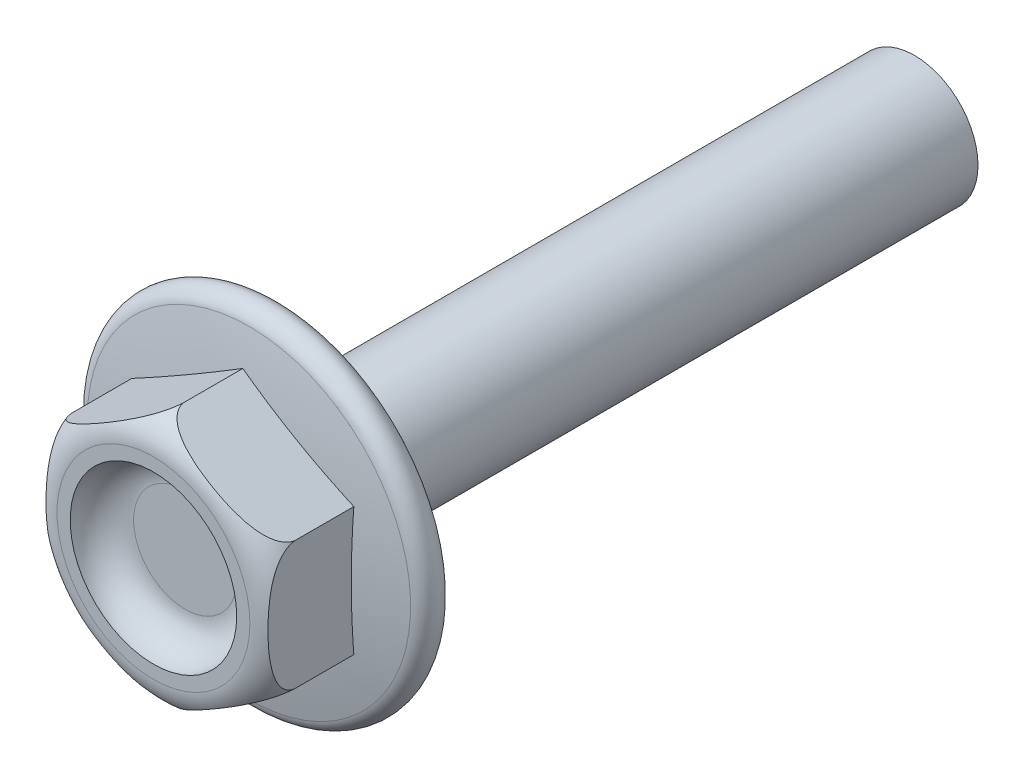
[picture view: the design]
ISO-10303-21;
HEADER;
FILE_DESCRIPTION(('STEP AP214'),'2;1');
FILE_NAME('part.step','',(''),(''),'','','');
FILE_SCHEMA(('AUTOMOTIVE_DESIGN { 1 0 10303 214 1 1 1 1 }'));
ENDSEC;
DATA;
#1=APPLICATION_CONTEXT('core data for automotive mechanical design processes');
#2=APPLICATION_PROTOCOL_DEFINITION('international standard','automotive_design',2000,#1);
#3=PRODUCT_CONTEXT('',#1,'mechanical');
#4=PRODUCT('Part','Part','',(#3));
#5=PRODUCT_RELATED_PRODUCT_CATEGORY('part','',(#4));
#6=PRODUCT_DEFINITION_FORMATION('','',#4);
#7=PRODUCT_DEFINITION_CONTEXT('part definition',#1,'design');
#8=PRODUCT_DEFINITION('design','',#6,#7);
#9=PRODUCT_DEFINITION_SHAPE('','',#8);
#10=(LENGTH_UNIT() NAMED_UNIT(*) SI_UNIT(.MILLI.,.METRE.));
#11=(NAMED_UNIT(*) PLANE_ANGLE_UNIT() SI_UNIT($,.RADIAN.));
#12=(NAMED_UNIT(*) SI_UNIT($,.STERADIAN.) SOLID_ANGLE_UNIT());
#13=UNCERTAINTY_MEASURE_WITH_UNIT(LENGTH_MEASURE(1.E-05),#10,'distance_accuracy_value','');
#14=(GEOMETRIC_REPRESENTATION_CONTEXT(3) GLOBAL_UNCERTAINTY_ASSIGNED_CONTEXT((#13)) GLOBAL_UNIT_ASSIGNED_CONTEXT((#10,
#11,#12)) REPRESENTATION_CONTEXT('',''));
#15=CARTESIAN_POINT('',(0.,0.,0.));
#16=DIRECTION('',(0.,0.,1.));
#17=DIRECTION('',(1.,0.,0.));
#18=AXIS2_PLACEMENT_3D('',#15,#16,#17);
#19=CARTESIAN_POINT('',(0.,4.04145188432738,4.));
#20=DIRECTION('',(0.500000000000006,0.866025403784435,0.));
#21=DIRECTION('',(-0.866025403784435,0.500000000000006,0.));
#22=AXIS2_PLACEMENT_3D('',#19,#20,#21);
#23=PLANE('',#22);
#24=DIRECTION('',(0.,0.,-1.));
#25=VECTOR('',#24,1.);
#26=CARTESIAN_POINT('',(0.,4.04145188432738,4.));
#27=LINE('',#26,#25);
#28=CARTESIAN_POINT('',(0.,4.04145188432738,3.));
#29=VERTEX_POINT('',#28);
#30=CARTESIAN_POINT('',(0.,4.04145188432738,1.18087034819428));
#31=VERTEX_POINT('',#30);
#32=EDGE_CURVE('E51',#29,#31,#27,.T.);
#33=ORIENTED_EDGE('',*,*,#32,.F.);
#34=CARTESIAN_POINT('',(3.46410156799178E-08,4.04145186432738,2.9998));
#35=CARTESIAN_POINT('',(-6.54132162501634E-05,4.04148965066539,3.02946004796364));
#36=CARTESIAN_POINT('',(0.00226144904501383,4.04014623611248,3.05905658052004));
#37=CARTESIAN_POINT('',(0.0112266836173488,4.03497015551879,3.11713737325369));
#38=CARTESIAN_POINT('',(0.0178312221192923,4.03115702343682,3.14562851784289));
#39=CARTESIAN_POINT('',(0.0348712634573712,4.02131895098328,3.20093447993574));
#40=CARTESIAN_POINT('',(0.0452976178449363,4.01529929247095,3.22775312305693));
#41=CARTESIAN_POINT('',(0.0693600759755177,4.0014068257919,3.27943202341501));
#42=CARTESIAN_POINT('',(0.0830027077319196,3.99353024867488,3.30428815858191));
#43=CARTESIAN_POINT('',(0.121428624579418,3.97134503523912,3.36543474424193));
#44=CARTESIAN_POINT('',(0.148119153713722,3.95593525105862,3.40012716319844));
#45=CARTESIAN_POINT('',(0.205872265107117,3.9225914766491,3.46423943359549));
#46=CARTESIAN_POINT('',(0.23694539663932,3.90465139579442,3.49364616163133));
#47=CARTESIAN_POINT('',(0.323036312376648,3.85494678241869,3.5651961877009));
#48=CARTESIAN_POINT('',(0.380554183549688,3.82173882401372,3.60329409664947));
#49=CARTESIAN_POINT('',(0.499668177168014,3.75296832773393,3.66943708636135));
#50=CARTESIAN_POINT('',(0.561272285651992,3.71740117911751,3.69746175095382));
#51=CARTESIAN_POINT('',(0.70657163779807,3.6335125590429,3.75351666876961));
#52=CARTESIAN_POINT('',(0.791067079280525,3.5847290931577,3.77871981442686));
#53=CARTESIAN_POINT('',(0.961803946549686,3.48615411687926,3.81977186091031));
#54=CARTESIAN_POINT('',(1.04804876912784,3.43636064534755,3.83560030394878));
#55=CARTESIAN_POINT('',(1.22192619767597,3.33597246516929,3.8605608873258));
#56=CARTESIAN_POINT('',(1.3095643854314,3.2853745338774,3.86963887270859));
#57=CARTESIAN_POINT('',(1.48502337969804,3.18407323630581,3.88252309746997));
#58=CARTESIAN_POINT('',(1.57284392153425,3.13337002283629,3.88633451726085));
#59=CARTESIAN_POINT('',(1.75592877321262,3.02766593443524,3.88956421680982));
#60=CARTESIAN_POINT('',(1.85119817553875,2.97266211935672,3.88858622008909));
#61=CARTESIAN_POINT('',(2.04168348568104,2.86268537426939,3.88109833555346));
#62=CARTESIAN_POINT('',(2.1368992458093,2.80771252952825,3.87458294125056));
#63=CARTESIAN_POINT('',(2.32594109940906,2.69856916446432,3.85466572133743));
#64=CARTESIAN_POINT('',(2.41977196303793,2.64439589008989,3.84132691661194));
#65=CARTESIAN_POINT('',(2.60599333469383,2.53688093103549,3.80514232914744));
#66=CARTESIAN_POINT('',(2.69838642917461,2.48353775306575,3.78231634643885));
#67=CARTESIAN_POINT('',(2.8368207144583,2.40361268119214,3.73693902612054));
#68=CARTESIAN_POINT('',(2.88407819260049,2.37632856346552,3.71938388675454));
#69=CARTESIAN_POINT('',(2.97718566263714,2.3225729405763,3.67952045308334));
#70=CARTESIAN_POINT('',(3.02303335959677,2.29610276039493,3.65720483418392));
#71=CARTESIAN_POINT('',(3.1126878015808,2.2443407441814,3.60659866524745));
#72=CARTESIAN_POINT('',(3.15647528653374,2.21906002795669,3.57826174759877));
#73=CARTESIAN_POINT('',(3.24002372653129,2.17082331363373,3.5144939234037));
#74=CARTESIAN_POINT('',(3.27979325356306,2.14786236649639,3.47907862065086));
#75=CARTESIAN_POINT('',(3.33931362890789,2.11349826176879,3.4146055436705));
#76=CARTESIAN_POINT('',(3.36104751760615,2.10095019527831,3.38800019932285));
#77=CARTESIAN_POINT('',(3.40092876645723,2.07792474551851,3.33138585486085));
#78=CARTESIAN_POINT('',(3.41907945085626,2.06744544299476,3.30138005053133));
#79=CARTESIAN_POINT('',(3.44834249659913,2.0505504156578,3.24278652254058));
#80=CARTESIAN_POINT('',(3.46009477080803,2.04376523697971,3.21462807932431));
#81=CARTESIAN_POINT('',(3.47936142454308,2.03264162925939,3.15645553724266));
#82=CARTESIAN_POINT('',(3.48688485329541,2.028297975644,3.12644555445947));
#83=CARTESIAN_POINT('',(3.49465097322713,2.02381420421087,3.08009860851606));
#84=CARTESIAN_POINT('',(3.49665509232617,2.02265712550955,3.06413628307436));
#85=CARTESIAN_POINT('',(3.49933449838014,2.02111016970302,3.03205266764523));
#86=CARTESIAN_POINT('',(3.50000884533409,2.02072083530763,3.01593127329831));
#87=CARTESIAN_POINT('',(3.49999996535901,2.02072596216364,2.9998));
#88=B_SPLINE_CURVE_WITH_KNOTS('',3,(#34,#35,#36,#37,#38,#39,#40,#41,#42,#43,#44,#45,#46,#47,#48,
#49,#50,#51,#52,#53,#54,#55,#56,#57,#58,#59,#60,#61,#62,#63,#64,#65,#66,#67,#68,#69,#70,#71,#72,
#73,#74,#75,#76,#77,#78,#79,#80,#81,#82,#83,#84,#85,#86,#87),.UNSPECIFIED.,.F.,.F.,(4,2,2,2,2,2,
2,2,2,2,2,2,2,2,2,2,2,2,2,2,2,2,2,2,2,2,4),(0.,0.0887549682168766,0.176816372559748,
0.264668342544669,0.352700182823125,0.491116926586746,0.629872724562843,0.858271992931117,
1.08713159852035,1.38870326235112,1.69093062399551,1.99555716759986,2.29988385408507,
2.62979570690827,2.96003601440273,3.28727986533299,3.61384415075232,3.78564861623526,
3.95771935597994,4.13116655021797,4.30423552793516,4.41365097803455,4.52296443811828,
4.61636709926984,4.70956912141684,4.75789060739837,4.8062462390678),.UNSPECIFIED.);
#89=CARTESIAN_POINT('',(3.49999999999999,2.0207259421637,3.));
#90=VERTEX_POINT('',#89);
#91=EDGE_CURVE('E44',#29,#90,#88,.T.);
#92=ORIENTED_EDGE('',*,*,#91,.T.);
#93=DIRECTION('',(0.,0.,-1.));
#94=VECTOR('',#93,1.);
#95=CARTESIAN_POINT('',(3.49999999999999,2.02072594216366,4.));
#96=LINE('',#95,#94);
#97=CARTESIAN_POINT('',(3.49999999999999,2.02072594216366,1.18087034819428));
#98=VERTEX_POINT('',#97);
#99=EDGE_CURVE('E92',#90,#98,#96,.T.);
#100=ORIENTED_EDGE('',*,*,#99,.T.);
#101=CARTESIAN_POINT('',(1.75000000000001,3.0310889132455,-24.25));
#102=DIRECTION('',(0.500000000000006,0.866025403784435,0.));
#103=DIRECTION('',(-0.866025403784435,0.500000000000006,0.));
#104=AXIS2_PLACEMENT_3D('',#101,#102,#103);
#105=CIRCLE('',#104,25.5110270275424);
#106=EDGE_CURVE('E111',#98,#31,#105,.F.);
#107=ORIENTED_EDGE('',*,*,#106,.T.);
#108=EDGE_LOOP('',(#33,#92,#100,#107));
#109=FACE_BOUND('',#108,.T.);
#110=ADVANCED_FACE('F28',(#109),#23,.T.);
#111=CARTESIAN_POINT('',(3.49999999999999,2.02072594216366,4.));
#112=DIRECTION('',(1.,0.,0.));
#113=DIRECTION('',(0.,1.,0.));
#114=AXIS2_PLACEMENT_3D('',#111,#112,#113);
#115=PLANE('',#114);
#116=ORIENTED_EDGE('',*,*,#99,.F.);
#117=CARTESIAN_POINT('',(3.49999999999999,0.,3.88866958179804));
#118=CARTESIAN_POINT('',(3.49999999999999,-0.0863268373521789,3.88866475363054));
#119=CARTESIAN_POINT('',(3.49999999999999,-0.172651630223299,3.88703903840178));
#120=CARTESIAN_POINT('',(3.49999999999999,-0.345200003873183,3.88029865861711));
#121=CARTESIAN_POINT('',(3.49999999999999,-0.431423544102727,3.87518289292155));
#122=CARTESIAN_POINT('',(3.49999999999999,-0.603354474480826,3.86079550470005));
#123=CARTESIAN_POINT('',(3.49999999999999,-0.689062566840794,3.85153259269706));
#124=CARTESIAN_POINT('',(3.49999999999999,-0.859711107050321,3.82768385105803));
#125=CARTESIAN_POINT('',(3.49999999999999,-0.944652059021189,3.81310182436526));
#126=CARTESIAN_POINT('',(3.49999999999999,-1.10047939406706,3.77956527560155));
#127=CARTESIAN_POINT('',(3.49999999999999,-1.17157101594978,3.7615884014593));
#128=CARTESIAN_POINT('',(3.49999999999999,-1.31198004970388,3.71895615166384));
#129=CARTESIAN_POINT('',(3.49999999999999,-1.38129291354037,3.69428522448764));
#130=CARTESIAN_POINT('',(3.49999999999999,-1.51730819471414,3.63592514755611));
#131=CARTESIAN_POINT('',(3.49999999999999,-1.58395793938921,3.60210997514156));
#132=CARTESIAN_POINT('',(3.49999999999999,-1.71012924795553,3.52311771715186));
#133=CARTESIAN_POINT('',(3.49999999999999,-1.76969019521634,3.47800819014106));
#134=CARTESIAN_POINT('',(3.49999999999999,-1.84774561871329,3.40145225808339));
#135=CARTESIAN_POINT('',(3.49999999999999,-1.87138500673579,3.3752636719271));
#136=CARTESIAN_POINT('',(3.49999999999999,-1.91465839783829,3.31970869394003));
#137=CARTESIAN_POINT('',(3.49999999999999,-1.93429275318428,3.2903425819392));
#138=CARTESIAN_POINT('',(3.49999999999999,-1.96851600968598,3.228316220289));
#139=CARTESIAN_POINT('',(3.49999999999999,-1.98304564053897,3.19562261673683));
#140=CARTESIAN_POINT('',(3.49999999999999,-2.0054250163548,3.12802070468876));
#141=CARTESIAN_POINT('',(3.49999999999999,-2.01328508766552,3.09311591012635));
#142=CARTESIAN_POINT('',(3.49999999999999,-2.02095945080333,3.02693329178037));
#143=CARTESIAN_POINT('',(3.49999999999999,-2.02166949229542,2.99575843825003));
#144=CARTESIAN_POINT('',(3.49999999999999,-2.01730141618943,2.93381941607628));
#145=CARTESIAN_POINT('',(3.49999999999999,-2.01222343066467,2.90305523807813));
#146=CARTESIAN_POINT('',(3.49999999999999,-1.99739983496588,2.84550196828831));
#147=CARTESIAN_POINT('',(3.49999999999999,-1.98808984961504,2.81859776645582));
#148=CARTESIAN_POINT('',(3.49999999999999,-1.96561338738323,2.76647205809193));
#149=CARTESIAN_POINT('',(3.49999999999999,-1.95244609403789,2.74125090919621));
#150=CARTESIAN_POINT('',(3.49999999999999,-1.91585963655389,2.68119414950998));
#151=CARTESIAN_POINT('',(3.49999999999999,-1.89054654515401,2.64751269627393));
#152=CARTESIAN_POINT('',(3.49999999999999,-1.83488053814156,2.58459756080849));
#153=CARTESIAN_POINT('',(3.49999999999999,-1.80451416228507,2.55537616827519));
#154=CARTESIAN_POINT('',(3.49999999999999,-1.72189631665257,2.48560726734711));
#155=CARTESIAN_POINT('',(3.49999999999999,-1.66706197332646,2.4481420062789));
#156=CARTESIAN_POINT('',(3.49999999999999,-1.55256598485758,2.38180725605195));
#157=CARTESIAN_POINT('',(3.49999999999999,-1.49289865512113,2.35294808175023));
#158=CARTESIAN_POINT('',(3.49999999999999,-1.3721212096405,2.30262557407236));
#159=CARTESIAN_POINT('',(3.49999999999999,-1.31107157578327,2.28101370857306));
#160=CARTESIAN_POINT('',(3.49999999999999,-1.18734677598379,2.24298388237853));
#161=CARTESIAN_POINT('',(3.49999999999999,-1.12466994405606,2.22657149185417));
#162=CARTESIAN_POINT('',(3.49999999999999,-0.997959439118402,2.19781531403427));
#163=CARTESIAN_POINT('',(3.49999999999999,-0.933919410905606,2.18550018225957));
#164=CARTESIAN_POINT('',(3.49999999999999,-0.805330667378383,2.16427101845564));
#165=CARTESIAN_POINT('',(3.49999999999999,-0.740782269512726,2.15535501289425));
#166=CARTESIAN_POINT('',(3.49999999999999,-0.598058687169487,2.13873267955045));
#167=CARTESIAN_POINT('',(3.49999999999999,-0.519811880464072,2.13165251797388));
#168=CARTESIAN_POINT('',(3.49999999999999,-0.36308132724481,2.12073868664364));
#169=CARTESIAN_POINT('',(3.49999999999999,-0.284597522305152,2.11690589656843));
#170=CARTESIAN_POINT('',(3.49999999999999,-0.127339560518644,2.11205625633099));
#171=CARTESIAN_POINT('',(3.49999999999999,-0.0485651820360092,2.11104681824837));
#172=CARTESIAN_POINT('',(3.49999999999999,0.108959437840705,2.11174847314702));
#173=CARTESIAN_POINT('',(3.49999999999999,0.18770968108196,2.11345913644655));
#174=CARTESIAN_POINT('',(3.49999999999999,0.344482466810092,2.11977175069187));
#175=CARTESIAN_POINT('',(3.49999999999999,0.42250589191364,2.12435103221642));
#176=CARTESIAN_POINT('',(3.49999999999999,0.578320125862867,2.13688479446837));
#177=CARTESIAN_POINT('',(3.49999999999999,0.656110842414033,2.14484047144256));
#178=CARTESIAN_POINT('',(3.49999999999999,0.810862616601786,2.1649235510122));
#179=CARTESIAN_POINT('',(3.49999999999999,0.887825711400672,2.17703484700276));
#180=CARTESIAN_POINT('',(3.49999999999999,1.04069181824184,2.20662161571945));
#181=CARTESIAN_POINT('',(3.49999999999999,1.11659576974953,2.22409197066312));
#182=CARTESIAN_POINT('',(3.49999999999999,1.22622138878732,2.25478752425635));
#183=CARTESIAN_POINT('',(3.49999999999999,1.26071408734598,2.26525722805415));
#184=CARTESIAN_POINT('',(3.49999999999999,1.32913620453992,2.28791589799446));
#185=CARTESIAN_POINT('',(3.49999999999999,1.36306544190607,2.30010540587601));
#186=CARTESIAN_POINT('',(3.49999999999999,1.46365216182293,2.33955916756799));
#187=CARTESIAN_POINT('',(3.49999999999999,1.52924178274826,2.369743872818));
#188=CARTESIAN_POINT('',(3.49999999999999,1.63826125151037,2.43070580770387));
#189=CARTESIAN_POINT('',(3.49999999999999,1.68295511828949,2.45920328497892));
#190=CARTESIAN_POINT('',(3.49999999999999,1.76768051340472,2.52254240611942));
#191=CARTESIAN_POINT('',(3.49999999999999,1.8077188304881,2.55737461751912));
#192=CARTESIAN_POINT('',(3.49999999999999,1.86880478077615,2.62179662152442));
#193=CARTESIAN_POINT('',(3.49999999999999,1.89183062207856,2.64950003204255));
#194=CARTESIAN_POINT('',(3.49999999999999,1.93330435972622,2.70815552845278));
#195=CARTESIAN_POINT('',(3.49999999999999,1.95175915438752,2.73910261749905));
#196=CARTESIAN_POINT('',(3.49999999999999,1.98020381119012,2.79847583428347));
#197=CARTESIAN_POINT('',(3.49999999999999,1.99108975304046,2.8264695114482));
#198=CARTESIAN_POINT('',(3.49999999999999,2.00802811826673,2.88389269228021));
#199=CARTESIAN_POINT('',(3.49999999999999,2.01408338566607,2.91332134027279));
#200=CARTESIAN_POINT('',(3.49999999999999,2.02088735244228,2.9729068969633));
#201=CARTESIAN_POINT('',(3.49999999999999,2.02161631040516,3.00306609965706));
#202=CARTESIAN_POINT('',(3.49999999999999,2.01765062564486,3.06302342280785));
#203=CARTESIAN_POINT('',(3.49999999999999,2.01295539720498,3.09282150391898));
#204=CARTESIAN_POINT('',(3.49999999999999,1.99894363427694,3.14951865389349));
#205=CARTESIAN_POINT('',(3.49999999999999,1.98990016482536,3.17648665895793));
#206=CARTESIAN_POINT('',(3.49999999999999,1.96792176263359,3.22877122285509));
#207=CARTESIAN_POINT('',(3.49999999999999,1.95498534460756,3.25408714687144));
#208=CARTESIAN_POINT('',(3.49999999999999,1.91910314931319,3.31410022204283));
#209=CARTESIAN_POINT('',(3.49999999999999,1.89430007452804,3.34768656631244));
#210=CARTESIAN_POINT('',(3.49999999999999,1.83966536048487,3.41047531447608));
#211=CARTESIAN_POINT('',(3.49999999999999,1.80982214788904,3.43966732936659));
#212=CARTESIAN_POINT('',(3.49999999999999,1.72878496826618,3.50921588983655));
#213=CARTESIAN_POINT('',(3.49999999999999,1.67504338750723,3.54658123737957));
#214=CARTESIAN_POINT('',(3.49999999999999,1.56265233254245,3.61290679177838));
#215=CARTESIAN_POINT('',(3.49999999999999,1.50399107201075,3.64184602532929));
#216=CARTESIAN_POINT('',(3.49999999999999,1.38547326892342,3.69227368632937));
#217=CARTESIAN_POINT('',(3.49999999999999,1.32569142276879,3.71394172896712));
#218=CARTESIAN_POINT('',(3.49999999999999,1.20448970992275,3.75217091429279));
#219=CARTESIAN_POINT('',(3.49999999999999,1.14306820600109,3.76872672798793));
#220=CARTESIAN_POINT('',(3.49999999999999,1.01920506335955,3.79774633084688));
#221=CARTESIAN_POINT('',(3.49999999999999,0.956762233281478,3.81020492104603));
#222=CARTESIAN_POINT('',(3.49999999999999,0.83129623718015,3.83179537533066));
#223=CARTESIAN_POINT('',(3.49999999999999,0.768272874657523,3.84092606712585));
#224=CARTESIAN_POINT('',(3.49999999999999,0.588181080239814,3.86310397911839));
#225=CARTESIAN_POINT('',(3.49999999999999,0.470713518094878,3.8728822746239));
#226=CARTESIAN_POINT('',(3.49999999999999,0.235495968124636,3.88566728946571));
#227=CARTESIAN_POINT('',(3.49999999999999,0.117746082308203,3.88867616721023));
#228=CARTESIAN_POINT('',(3.49999999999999,0.,3.88866958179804));
#229=B_SPLINE_CURVE_WITH_KNOTS('',3,(#117,#118,#119,#120,#121,#122,#123,#124,#125,#126,#127,
#128,#129,#130,#131,#132,#133,#134,#135,#136,#137,#138,#139,#140,#141,#142,#143,#144,#145,#146,
#147,#148,#149,#150,#151,#152,#153,#154,#155,#156,#157,#158,#159,#160,#161,#162,#163,#164,#165,
#166,#167,#168,#169,#170,#171,#172,#173,#174,#175,#176,#177,#178,#179,#180,#181,#182,#183,#184,
#185,#186,#187,#188,#189,#190,#191,#192,#193,#194,#195,#196,#197,#198,#199,#200,#201,#202,#203,
#204,#205,#206,#207,#208,#209,#210,#211,#212,#213,#214,#215,#216,#217,#218,#219,#220,#221,#222,
#223,#224,#225,#226,#227,#228),.UNSPECIFIED.,.T.,.F.,(4,2,2,2,2,2,2,2,2,2,2,2,2,2,2,2,2,2,2,2,2,
2,2,2,2,2,2,2,2,2,2,2,2,2,2,2,2,2,2,2,2,2,2,2,2,2,2,2,2,2,2,2,2,2,2,4),(0.,0.258960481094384,
0.518002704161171,0.776503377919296,1.03481959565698,1.25457530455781,1.47484598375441,
1.69832240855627,1.92049274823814,2.02603918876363,2.13157634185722,2.23830124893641,
2.34486061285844,2.43787441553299,2.53088609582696,2.61595499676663,2.7010419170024,
2.82672538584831,2.95274915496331,3.15085859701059,3.34920453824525,3.54319361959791,
3.73738982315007,3.93291697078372,4.12833042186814,4.36394350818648,4.59962039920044,
4.83591542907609,5.07217313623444,5.30658695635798,5.5410838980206,5.77468204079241,
6.0080577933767,6.11615522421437,6.22428678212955,6.44013860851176,6.59875051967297,
6.75712816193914,6.86485155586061,6.9724113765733,7.06214192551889,7.15181960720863,
7.24182950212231,7.33184911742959,7.4168355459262,7.50185444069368,7.62640196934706,
7.75123947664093,7.94649755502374,8.14223757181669,8.33270789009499,8.52337608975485,
8.71428530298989,8.9052617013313,9.25858529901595,9.61179622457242),.UNSPECIFIED.);
#230=CARTESIAN_POINT('',(3.49999999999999,-2.0207259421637,3.));
#231=VERTEX_POINT('',#230);
#232=EDGE_CURVE('E81',#90,#231,#229,.T.);
#233=ORIENTED_EDGE('',*,*,#232,.T.);
#234=DIRECTION('',(0.,0.,-1.));
#235=VECTOR('',#234,1.);
#236=CARTESIAN_POINT('',(3.49999999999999,-2.0207259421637,4.));
#237=LINE('',#236,#235);
#238=CARTESIAN_POINT('',(3.49999999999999,-2.0207259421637,1.18087034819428));
#239=VERTEX_POINT('',#238);
#240=EDGE_CURVE('E100',#231,#239,#237,.T.);
#241=ORIENTED_EDGE('',*,*,#240,.T.);
#242=CARTESIAN_POINT('',(3.49999999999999,0.,-24.25));
#243=DIRECTION('',(1.,0.,0.));
#244=DIRECTION('',(0.,1.,0.));
#245=AXIS2_PLACEMENT_3D('',#242,#243,#244);
#246=CIRCLE('',#245,25.5110270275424);
#247=EDGE_CURVE('E99',#239,#98,#246,.F.);
#248=ORIENTED_EDGE('',*,*,#247,.T.);
#249=EDGE_LOOP('',(#116,#233,#241,#248));
#250=FACE_BOUND('',#249,.T.);
#251=ADVANCED_FACE('F97',(#250),#115,.T.);
#252=CARTESIAN_POINT('',(3.49999999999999,-2.0207259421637,4.));
#253=DIRECTION('',(0.499999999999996,-0.866025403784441,0.));
#254=DIRECTION('',(0.866025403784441,0.499999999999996,0.));
#255=AXIS2_PLACEMENT_3D('',#252,#253,#254);
#256=PLANE('',#255);
#257=ORIENTED_EDGE('',*,*,#240,.F.);
#258=CARTESIAN_POINT('',(3.49999996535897,-2.0207259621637,2.9998));
#259=CARTESIAN_POINT('',(3.50006541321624,-2.02068817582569,3.02946004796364));
#260=CARTESIAN_POINT('',(3.49773855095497,-2.0220315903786,3.05905658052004));
#261=CARTESIAN_POINT('',(3.48877331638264,-2.02720767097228,3.11713737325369));
#262=CARTESIAN_POINT('',(3.48216877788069,-2.03102080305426,3.14562851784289));
#263=CARTESIAN_POINT('',(3.46512873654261,-2.0408588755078,3.20093447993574));
#264=CARTESIAN_POINT('',(3.45470238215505,-2.04687853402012,3.22775312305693));
#265=CARTESIAN_POINT('',(3.43063992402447,-2.06077100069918,3.27943202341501));
#266=CARTESIAN_POINT('',(3.41699729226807,-2.06864757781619,3.3042881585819));
#267=CARTESIAN_POINT('',(3.37857137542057,-2.09083279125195,3.36543474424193));
#268=CARTESIAN_POINT('',(3.35188084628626,-2.10624257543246,3.40012716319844));
#269=CARTESIAN_POINT('',(3.29412773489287,-2.13958634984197,3.46423943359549));
#270=CARTESIAN_POINT('',(3.26305460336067,-2.15752643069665,3.49364616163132));
#271=CARTESIAN_POINT('',(3.17696368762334,-2.20723104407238,3.56519618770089));
#272=CARTESIAN_POINT('',(3.1194458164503,-2.24043900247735,3.60329409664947));
#273=CARTESIAN_POINT('',(3.00033182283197,-2.30920949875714,3.66943708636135));
#274=CARTESIAN_POINT('',(2.93872771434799,-2.34477664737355,3.69746175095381));
#275=CARTESIAN_POINT('',(2.79342836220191,-2.42866526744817,3.75351666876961));
#276=CARTESIAN_POINT('',(2.70893292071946,-2.47744873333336,3.77871981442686));
#277=CARTESIAN_POINT('',(2.5381960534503,-2.5760237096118,3.8197718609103));
#278=CARTESIAN_POINT('',(2.45195123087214,-2.62581718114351,3.83560030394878));
#279=CARTESIAN_POINT('',(2.27807380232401,-2.72620536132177,3.86056088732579));
#280=CARTESIAN_POINT('',(2.19043561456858,-2.77680329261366,3.86963887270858));
#281=CARTESIAN_POINT('',(2.01497662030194,-2.87810459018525,3.88252309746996));
#282=CARTESIAN_POINT('',(1.92715607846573,-2.92880780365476,3.88633451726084));
#283=CARTESIAN_POINT('',(1.74407122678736,-3.03451189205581,3.88956421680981));
#284=CARTESIAN_POINT('',(1.64880182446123,-3.08951570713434,3.88858622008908));
#285=CARTESIAN_POINT('',(1.45831651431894,-3.19949245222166,3.88109833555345));
#286=CARTESIAN_POINT('',(1.36310075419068,-3.2544652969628,3.87458294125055));
#287=CARTESIAN_POINT('',(1.17405890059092,-3.36360866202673,3.85466572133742));
#288=CARTESIAN_POINT('',(1.08022803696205,-3.41778193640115,3.84132691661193));
#289=CARTESIAN_POINT('',(0.894006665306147,-3.52529689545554,3.80514232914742));
#290=CARTESIAN_POINT('',(0.801613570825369,-3.57864007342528,3.78231634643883));
#291=CARTESIAN_POINT('',(0.663179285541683,-3.65856514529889,3.73693902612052));
#292=CARTESIAN_POINT('',(0.615921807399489,-3.68584926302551,3.71938388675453));
#293=CARTESIAN_POINT('',(0.522814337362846,-3.73960488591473,3.67952045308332));
#294=CARTESIAN_POINT('',(0.476966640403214,-3.7660750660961,3.65720483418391));
#295=CARTESIAN_POINT('',(0.387312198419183,-3.81783708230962,3.60659866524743));
#296=CARTESIAN_POINT('',(0.34352471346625,-3.84311779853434,3.57826174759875));
#297=CARTESIAN_POINT('',(0.259976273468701,-3.89135451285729,3.51449392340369));
#298=CARTESIAN_POINT('',(0.22020674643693,-3.91431545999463,3.47907862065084));
#299=CARTESIAN_POINT('',(0.160686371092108,-3.94867956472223,3.41460554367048));
#300=CARTESIAN_POINT('',(0.138952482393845,-3.96122763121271,3.38800019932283));
#301=CARTESIAN_POINT('',(0.0990712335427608,-3.9842530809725,3.33138585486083));
#302=CARTESIAN_POINT('',(0.0809205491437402,-3.99473238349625,3.30138005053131));
#303=CARTESIAN_POINT('',(0.0516575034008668,-4.01162741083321,3.24278652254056));
#304=CARTESIAN_POINT('',(0.0399052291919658,-4.01841258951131,3.21462807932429));
#305=CARTESIAN_POINT('',(0.0206385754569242,-4.02953619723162,3.15645553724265));
#306=CARTESIAN_POINT('',(0.0131151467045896,-4.03387985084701,3.12644555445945));
#307=CARTESIAN_POINT('',(0.0053490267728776,-4.03836362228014,3.08009860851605));
#308=CARTESIAN_POINT('',(0.00334490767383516,-4.03952070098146,3.06413628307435));
#309=CARTESIAN_POINT('',(0.00066550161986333,-4.04106765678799,3.03205266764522));
#310=CARTESIAN_POINT('',(-8.84533408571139E-06,-4.04145699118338,3.01593127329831));
#311=CARTESIAN_POINT('',(3.46409954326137E-08,-4.04145186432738,2.9998));
#312=B_SPLINE_CURVE_WITH_KNOTS('',3,(#258,#259,#260,#261,#262,#263,#264,#265,#266,#267,#268,
#269,#270,#271,#272,#273,#274,#275,#276,#277,#278,#279,#280,#281,#282,#283,#284,#285,#286,#287,
#288,#289,#290,#291,#292,#293,#294,#295,#296,#297,#298,#299,#300,#301,#302,#303,#304,#305,#306,
#307,#308,#309,#310,#311),.UNSPECIFIED.,.F.,.F.,(4,2,2,2,2,2,2,2,2,2,2,2,2,2,2,2,2,2,2,2,2,2,2,
2,2,2,4),(0.,0.088754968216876,0.176816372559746,0.264668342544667,0.352700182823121,
0.491116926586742,0.629872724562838,0.858271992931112,1.08713159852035,1.38870326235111,
1.69093062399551,1.99555716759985,2.29988385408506,2.62979570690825,2.96003601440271,
3.28727986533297,3.6138441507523,3.78564861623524,3.95771935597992,4.13116655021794,
4.30423552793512,4.41365097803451,4.52296443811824,4.61636709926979,4.70956912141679,
4.75789060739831,4.80624623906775),.UNSPECIFIED.);
#313=CARTESIAN_POINT('',(0.,-4.04145188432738,3.));
#314=VERTEX_POINT('',#313);
#315=EDGE_CURVE('E85',#231,#314,#312,.T.);
#316=ORIENTED_EDGE('',*,*,#315,.T.);
#317=DIRECTION('',(0.,0.,-1.));
#318=VECTOR('',#317,1.);
#319=CARTESIAN_POINT('',(0.,-4.04145188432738,4.));
#320=LINE('',#319,#318);
#321=CARTESIAN_POINT('',(0.,-4.04145188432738,1.18087034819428));
#322=VERTEX_POINT('',#321);
#323=EDGE_CURVE('E102',#314,#322,#320,.T.);
#324=ORIENTED_EDGE('',*,*,#323,.T.);
#325=CARTESIAN_POINT('',(1.74999999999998,-3.03108891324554,-24.25));
#326=DIRECTION('',(0.499999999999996,-0.866025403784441,0.));
#327=DIRECTION('',(0.866025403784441,0.499999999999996,0.));
#328=AXIS2_PLACEMENT_3D('',#325,#326,#327);
#329=CIRCLE('',#328,25.5110270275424);
#330=EDGE_CURVE('E256',#322,#239,#329,.F.);
#331=ORIENTED_EDGE('',*,*,#330,.T.);
#332=EDGE_LOOP('',(#257,#316,#324,#331));
#333=FACE_BOUND('',#332,.T.);
#334=ADVANCED_FACE('F157',(#333),#256,.T.);
#335=CARTESIAN_POINT('',(0.,-4.04145188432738,4.));
#336=DIRECTION('',(-0.499999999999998,-0.86602540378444,0.));
#337=DIRECTION('',(0.86602540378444,-0.499999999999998,0.));
#338=AXIS2_PLACEMENT_3D('',#335,#336,#337);
#339=PLANE('',#338);
#340=ORIENTED_EDGE('',*,*,#323,.F.);
#341=CARTESIAN_POINT('',(-3.4641037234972E-08,-4.04145186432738,2.9998));
#342=CARTESIAN_POINT('',(6.54132162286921E-05,-4.04148965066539,3.02946004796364));
#343=CARTESIAN_POINT('',(-0.00226144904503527,-4.04014623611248,3.05905658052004));
#344=CARTESIAN_POINT('',(-0.01122668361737,-4.03497015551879,3.11713737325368));
#345=CARTESIAN_POINT('',(-0.0178312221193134,-4.03115702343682,3.14562851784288));
#346=CARTESIAN_POINT('',(-0.0348712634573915,-4.02131895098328,3.20093447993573));
#347=CARTESIAN_POINT('',(-0.045297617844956,-4.01529929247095,3.22775312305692));
#348=CARTESIAN_POINT('',(-0.0693600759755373,-4.0014068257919,3.279432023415));
#349=CARTESIAN_POINT('',(-0.0830027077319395,-3.99353024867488,3.3042881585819));
#350=CARTESIAN_POINT('',(-0.121428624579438,-3.97134503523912,3.36543474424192));
#351=CARTESIAN_POINT('',(-0.148119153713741,-3.95593525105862,3.40012716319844));
#352=CARTESIAN_POINT('',(-0.205872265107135,-3.92259147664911,3.46423943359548));
#353=CARTESIAN_POINT('',(-0.236945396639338,-3.90465139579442,3.49364616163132));
#354=CARTESIAN_POINT('',(-0.323036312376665,-3.8549467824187,3.56519618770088));
#355=CARTESIAN_POINT('',(-0.380554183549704,-3.82173882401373,3.60329409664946));
#356=CARTESIAN_POINT('',(-0.499668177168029,-3.75296832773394,3.66943708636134));
#357=CARTESIAN_POINT('',(-0.561272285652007,-3.71740117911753,3.6974617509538));
#358=CARTESIAN_POINT('',(-0.706571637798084,-3.63351255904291,3.7535166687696));
#359=CARTESIAN_POINT('',(-0.791067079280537,-3.58472909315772,3.77871981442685));
#360=CARTESIAN_POINT('',(-0.961803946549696,-3.48615411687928,3.81977186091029));
#361=CARTESIAN_POINT('',(-1.04804876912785,-3.43636064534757,3.83560030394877));
#362=CARTESIAN_POINT('',(-1.22192619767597,-3.33597246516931,3.86056088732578));
#363=CARTESIAN_POINT('',(-1.3095643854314,-3.28537453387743,3.86963887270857));
#364=CARTESIAN_POINT('',(-1.48502337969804,-3.18407323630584,3.88252309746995));
#365=CARTESIAN_POINT('',(-1.57284392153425,-3.13337002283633,3.88633451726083));
#366=CARTESIAN_POINT('',(-1.75592877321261,-3.02766593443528,3.88956421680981));
#367=CARTESIAN_POINT('',(-1.85119817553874,-2.97266211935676,3.88858622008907));
#368=CARTESIAN_POINT('',(-2.04168348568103,-2.86268537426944,3.88109833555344));
#369=CARTESIAN_POINT('',(-2.13689924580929,-2.8077125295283,3.87458294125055));
#370=CARTESIAN_POINT('',(-2.32594109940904,-2.69856916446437,3.85466572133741));
#371=CARTESIAN_POINT('',(-2.41977196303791,-2.64439589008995,3.84132691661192));
#372=CARTESIAN_POINT('',(-2.60599333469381,-2.53688093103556,3.80514232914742));
#373=CARTESIAN_POINT('',(-2.69838642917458,-2.48353775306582,3.78231634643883));
#374=CARTESIAN_POINT('',(-2.83682071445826,-2.40361268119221,3.73693902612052));
#375=CARTESIAN_POINT('',(-2.88407819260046,-2.37632856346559,3.71938388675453));
#376=CARTESIAN_POINT('',(-2.9771856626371,-2.32257294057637,3.67952045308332));
#377=CARTESIAN_POINT('',(-3.02303335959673,-2.29610276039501,3.6572048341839));
#378=CARTESIAN_POINT('',(-3.11268780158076,-2.24434074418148,3.60659866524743));
#379=CARTESIAN_POINT('',(-3.1564752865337,-2.21906002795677,3.57826174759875));
#380=CARTESIAN_POINT('',(-3.24002372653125,-2.17082331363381,3.51449392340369));
#381=CARTESIAN_POINT('',(-3.27979325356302,-2.14786236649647,3.47907862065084));
#382=CARTESIAN_POINT('',(-3.33931362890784,-2.11349826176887,3.41460554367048));
#383=CARTESIAN_POINT('',(-3.3610475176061,-2.10095019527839,3.38800019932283));
#384=CARTESIAN_POINT('',(-3.40092876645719,-2.0779247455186,3.33138585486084));
#385=CARTESIAN_POINT('',(-3.41907945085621,-2.06744544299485,3.30138005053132));
#386=CARTESIAN_POINT('',(-3.44834249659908,-2.05055041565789,3.24278652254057));
#387=CARTESIAN_POINT('',(-3.46009477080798,-2.04376523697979,3.2146280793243));
#388=CARTESIAN_POINT('',(-3.47936142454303,-2.03264162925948,3.15645553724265));
#389=CARTESIAN_POINT('',(-3.48688485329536,-2.02829797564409,3.12644555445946));
#390=CARTESIAN_POINT('',(-3.49465097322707,-2.02381420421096,3.08009860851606));
#391=CARTESIAN_POINT('',(-3.49665509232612,-2.02265712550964,3.06413628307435));
#392=CARTESIAN_POINT('',(-3.49933449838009,-2.02111016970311,3.03205266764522));
#393=CARTESIAN_POINT('',(-3.50000884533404,-2.02072083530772,3.01593127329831));
#394=CARTESIAN_POINT('',(-3.49999996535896,-2.02072596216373,2.9998));
#395=B_SPLINE_CURVE_WITH_KNOTS('',3,(#341,#342,#343,#344,#345,#346,#347,#348,#349,#350,#351,
#352,#353,#354,#355,#356,#357,#358,#359,#360,#361,#362,#363,#364,#365,#366,#367,#368,#369,#370,
#371,#372,#373,#374,#375,#376,#377,#378,#379,#380,#381,#382,#383,#384,#385,#386,#387,#388,#389,
#390,#391,#392,#393,#394),.UNSPECIFIED.,.F.,.F.,(4,2,2,2,2,2,2,2,2,2,2,2,2,2,2,2,2,2,2,2,2,2,2,
2,2,2,4),(0.,0.0887549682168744,0.176816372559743,0.264668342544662,0.352700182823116,
0.491116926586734,0.629872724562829,0.858271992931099,1.08713159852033,1.38870326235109,
1.69093062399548,1.99555716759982,2.29988385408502,2.62979570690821,2.96003601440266,
3.28727986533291,3.61384415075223,3.78564861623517,3.95771935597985,4.13116655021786,
4.30423552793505,4.41365097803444,4.52296443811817,4.61636709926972,4.70956912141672,
4.75789060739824,4.80624623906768),.UNSPECIFIED.);
#396=CARTESIAN_POINT('',(-3.50000000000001,-2.02072594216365,3.));
#397=VERTEX_POINT('',#396);
#398=EDGE_CURVE('E138',#314,#397,#395,.T.);
#399=ORIENTED_EDGE('',*,*,#398,.T.);
#400=DIRECTION('',(0.,0.,-1.));
#401=VECTOR('',#400,1.);
#402=CARTESIAN_POINT('',(-3.50000000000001,-2.0207259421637,4.));
#403=LINE('',#402,#401);
#404=CARTESIAN_POINT('',(-3.50000000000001,-2.0207259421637,1.18087034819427));
#405=VERTEX_POINT('',#404);
#406=EDGE_CURVE('E244',#397,#405,#403,.T.);
#407=ORIENTED_EDGE('',*,*,#406,.T.);
#408=CARTESIAN_POINT('',(-1.75,-3.03108891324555,-24.25));
#409=DIRECTION('',(-0.499999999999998,-0.86602540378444,0.));
#410=DIRECTION('',(0.86602540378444,-0.499999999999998,0.));
#411=AXIS2_PLACEMENT_3D('',#408,#409,#410);
#412=CIRCLE('',#411,25.5110270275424);
#413=EDGE_CURVE('E243',#405,#322,#412,.F.);
#414=ORIENTED_EDGE('',*,*,#413,.T.);
#415=EDGE_LOOP('',(#340,#399,#407,#414));
#416=FACE_BOUND('',#415,.T.);
#417=ADVANCED_FACE('F178',(#416),#339,.T.);
#418=CARTESIAN_POINT('',(-3.50000000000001,-2.0207259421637,4.));
#419=DIRECTION('',(-1.,0.,0.));
#420=DIRECTION('',(0.,-1.,0.));
#421=AXIS2_PLACEMENT_3D('',#418,#419,#420);
#422=PLANE('',#421);
#423=ORIENTED_EDGE('',*,*,#406,.F.);
#424=CARTESIAN_POINT('',(-3.50000000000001,0.,3.88866958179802));
#425=CARTESIAN_POINT('',(-3.50000000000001,0.086326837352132,3.88866475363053));
#426=CARTESIAN_POINT('',(-3.50000000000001,0.172651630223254,3.88703903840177));
#427=CARTESIAN_POINT('',(-3.50000000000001,0.345200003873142,3.8802986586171));
#428=CARTESIAN_POINT('',(-3.50000000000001,0.431423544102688,3.87518289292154));
#429=CARTESIAN_POINT('',(-3.50000000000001,0.603354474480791,3.86079550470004));
#430=CARTESIAN_POINT('',(-3.50000000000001,0.689062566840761,3.85153259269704));
#431=CARTESIAN_POINT('',(-3.50000000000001,0.859711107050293,3.82768385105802));
#432=CARTESIAN_POINT('',(-3.50000000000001,0.944652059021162,3.81310182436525));
#433=CARTESIAN_POINT('',(-3.50000000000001,1.10047939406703,3.77956527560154));
#434=CARTESIAN_POINT('',(-3.50000000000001,1.17157101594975,3.76158840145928));
#435=CARTESIAN_POINT('',(-3.50000000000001,1.31198004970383,3.71895615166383));
#436=CARTESIAN_POINT('',(-3.50000000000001,1.38129291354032,3.69428522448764));
#437=CARTESIAN_POINT('',(-3.50000000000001,1.51730819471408,3.63592514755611));
#438=CARTESIAN_POINT('',(-3.50000000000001,1.58395793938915,3.60210997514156));
#439=CARTESIAN_POINT('',(-3.50000000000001,1.71012924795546,3.52311771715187));
#440=CARTESIAN_POINT('',(-3.50000000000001,1.76969019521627,3.47800819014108));
#441=CARTESIAN_POINT('',(-3.50000000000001,1.84774561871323,3.40145225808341));
#442=CARTESIAN_POINT('',(-3.50000000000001,1.87138500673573,3.37526367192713));
#443=CARTESIAN_POINT('',(-3.50000000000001,1.91465839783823,3.31970869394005));
#444=CARTESIAN_POINT('',(-3.50000000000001,1.93429275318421,3.29034258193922));
#445=CARTESIAN_POINT('',(-3.50000000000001,1.96851600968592,3.22831622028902));
#446=CARTESIAN_POINT('',(-3.50000000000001,1.98304564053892,3.19562261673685));
#447=CARTESIAN_POINT('',(-3.50000000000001,2.00542501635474,3.12802070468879));
#448=CARTESIAN_POINT('',(-3.50000000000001,2.01328508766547,3.09311591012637));
#449=CARTESIAN_POINT('',(-3.50000000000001,2.02095945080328,3.02693329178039));
#450=CARTESIAN_POINT('',(-3.50000000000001,2.02166949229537,2.99575843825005));
#451=CARTESIAN_POINT('',(-3.50000000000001,2.01730141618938,2.9338194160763));
#452=CARTESIAN_POINT('',(-3.50000000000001,2.01222343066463,2.90305523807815));
#453=CARTESIAN_POINT('',(-3.50000000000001,1.99739983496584,2.84550196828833));
#454=CARTESIAN_POINT('',(-3.50000000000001,1.988089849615,2.81859776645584));
#455=CARTESIAN_POINT('',(-3.50000000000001,1.9656133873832,2.76647205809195));
#456=CARTESIAN_POINT('',(-3.50000000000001,1.95244609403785,2.74125090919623));
#457=CARTESIAN_POINT('',(-3.50000000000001,1.91585963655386,2.68119414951));
#458=CARTESIAN_POINT('',(-3.50000000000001,1.89054654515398,2.64751269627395));
#459=CARTESIAN_POINT('',(-3.50000000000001,1.83488053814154,2.58459756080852));
#460=CARTESIAN_POINT('',(-3.50000000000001,1.80451416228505,2.55537616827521));
#461=CARTESIAN_POINT('',(-3.50000000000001,1.72189631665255,2.48560726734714));
#462=CARTESIAN_POINT('',(-3.50000000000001,1.66706197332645,2.44814200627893));
#463=CARTESIAN_POINT('',(-3.50000000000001,1.55256598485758,2.38180725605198));
#464=CARTESIAN_POINT('',(-3.50000000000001,1.49289865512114,2.35294808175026));
#465=CARTESIAN_POINT('',(-3.50000000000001,1.37212120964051,2.30262557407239));
#466=CARTESIAN_POINT('',(-3.50000000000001,1.31107157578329,2.28101370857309));
#467=CARTESIAN_POINT('',(-3.50000000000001,1.18734677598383,2.24298388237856));
#468=CARTESIAN_POINT('',(-3.50000000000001,1.1246699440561,2.2265714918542));
#469=CARTESIAN_POINT('',(-3.50000000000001,0.997959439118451,2.1978153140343));
#470=CARTESIAN_POINT('',(-3.50000000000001,0.93391941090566,2.1855001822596));
#471=CARTESIAN_POINT('',(-3.50000000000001,0.805330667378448,2.16427101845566));
#472=CARTESIAN_POINT('',(-3.50000000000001,0.740782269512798,2.15535501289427));
#473=CARTESIAN_POINT('',(-3.50000000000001,0.598058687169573,2.13873267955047));
#474=CARTESIAN_POINT('',(-3.50000000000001,0.519811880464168,2.1316525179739));
#475=CARTESIAN_POINT('',(-3.50000000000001,0.363081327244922,2.12073868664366));
#476=CARTESIAN_POINT('',(-3.50000000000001,0.284597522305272,2.11690589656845));
#477=CARTESIAN_POINT('',(-3.50000000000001,0.127339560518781,2.11205625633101));
#478=CARTESIAN_POINT('',(-3.50000000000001,0.0485651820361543,2.11104681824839));
#479=CARTESIAN_POINT('',(-3.50000000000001,-0.108959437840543,2.11174847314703));
#480=CARTESIAN_POINT('',(-3.50000000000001,-0.187709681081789,2.11345913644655));
#481=CARTESIAN_POINT('',(-3.50000000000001,-0.344482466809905,2.11977175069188));
#482=CARTESIAN_POINT('',(-3.50000000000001,-0.422505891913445,2.12435103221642));
#483=CARTESIAN_POINT('',(-3.50000000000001,-0.578320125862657,2.13688479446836));
#484=CARTESIAN_POINT('',(-3.50000000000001,-0.656110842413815,2.14484047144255));
#485=CARTESIAN_POINT('',(-3.50000000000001,-0.810862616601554,2.16492355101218));
#486=CARTESIAN_POINT('',(-3.50000000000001,-0.887825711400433,2.17703484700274));
#487=CARTESIAN_POINT('',(-3.50000000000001,-1.04069181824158,2.20662161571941));
#488=CARTESIAN_POINT('',(-3.50000000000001,-1.11659576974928,2.22409197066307));
#489=CARTESIAN_POINT('',(-3.50000000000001,-1.22622138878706,2.2547875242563));
#490=CARTESIAN_POINT('',(-3.50000000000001,-1.26071408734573,2.2652572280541));
#491=CARTESIAN_POINT('',(-3.50000000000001,-1.3291362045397,2.28791589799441));
#492=CARTESIAN_POINT('',(-3.50000000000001,-1.36306544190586,2.30010540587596));
#493=CARTESIAN_POINT('',(-3.50000000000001,-1.46365216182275,2.33955916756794));
#494=CARTESIAN_POINT('',(-3.50000000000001,-1.52924178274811,2.36974387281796));
#495=CARTESIAN_POINT('',(-3.50000000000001,-1.63826125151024,2.43070580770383));
#496=CARTESIAN_POINT('',(-3.50000000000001,-1.68295511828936,2.45920328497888));
#497=CARTESIAN_POINT('',(-3.50000000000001,-1.7676805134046,2.52254240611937));
#498=CARTESIAN_POINT('',(-3.50000000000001,-1.80771883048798,2.55737461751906));
#499=CARTESIAN_POINT('',(-3.50000000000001,-1.86880478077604,2.62179662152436));
#500=CARTESIAN_POINT('',(-3.50000000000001,-1.89183062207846,2.64950003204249));
#501=CARTESIAN_POINT('',(-3.50000000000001,-1.93330435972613,2.70815552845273));
#502=CARTESIAN_POINT('',(-3.50000000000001,-1.95175915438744,2.73910261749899));
#503=CARTESIAN_POINT('',(-3.50000000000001,-1.98020381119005,2.79847583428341));
#504=CARTESIAN_POINT('',(-3.50000000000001,-1.99108975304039,2.82646951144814));
#505=CARTESIAN_POINT('',(-3.50000000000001,-2.00802811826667,2.88389269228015));
#506=CARTESIAN_POINT('',(-3.50000000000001,-2.01408338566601,2.91332134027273));
#507=CARTESIAN_POINT('',(-3.50000000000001,-2.02088735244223,2.97290689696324));
#508=CARTESIAN_POINT('',(-3.50000000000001,-2.02161631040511,3.003066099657));
#509=CARTESIAN_POINT('',(-3.50000000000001,-2.01765062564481,3.0630234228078));
#510=CARTESIAN_POINT('',(-3.50000000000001,-2.01295539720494,3.09282150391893));
#511=CARTESIAN_POINT('',(-3.50000000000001,-1.99894363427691,3.14951865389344));
#512=CARTESIAN_POINT('',(-3.50000000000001,-1.98990016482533,3.17648665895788));
#513=CARTESIAN_POINT('',(-3.50000000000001,-1.96792176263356,3.22877122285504));
#514=CARTESIAN_POINT('',(-3.50000000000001,-1.95498534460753,3.25408714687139));
#515=CARTESIAN_POINT('',(-3.50000000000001,-1.91910314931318,3.31410022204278));
#516=CARTESIAN_POINT('',(-3.50000000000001,-1.89430007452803,3.34768656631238));
#517=CARTESIAN_POINT('',(-3.50000000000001,-1.83966536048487,3.41047531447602));
#518=CARTESIAN_POINT('',(-3.50000000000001,-1.80982214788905,3.43966732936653));
#519=CARTESIAN_POINT('',(-3.50000000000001,-1.7287849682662,3.50921588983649));
#520=CARTESIAN_POINT('',(-3.50000000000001,-1.67504338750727,3.54658123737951));
#521=CARTESIAN_POINT('',(-3.50000000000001,-1.56265233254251,3.61290679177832));
#522=CARTESIAN_POINT('',(-3.50000000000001,-1.50399107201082,3.64184602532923));
#523=CARTESIAN_POINT('',(-3.50000000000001,-1.38547326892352,3.6922736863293));
#524=CARTESIAN_POINT('',(-3.50000000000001,-1.3256914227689,3.71394172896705));
#525=CARTESIAN_POINT('',(-3.50000000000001,-1.20448970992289,3.75217091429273));
#526=CARTESIAN_POINT('',(-3.50000000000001,-1.14306820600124,3.76872672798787));
#527=CARTESIAN_POINT('',(-3.50000000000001,-1.01920506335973,3.79774633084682));
#528=CARTESIAN_POINT('',(-3.50000000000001,-0.956762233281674,3.81020492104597));
#529=CARTESIAN_POINT('',(-3.50000000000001,-0.831296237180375,3.83179537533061));
#530=CARTESIAN_POINT('',(-3.50000000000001,-0.768272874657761,3.8409260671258));
#531=CARTESIAN_POINT('',(-3.50000000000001,-0.588181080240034,3.86310397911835));
#532=CARTESIAN_POINT('',(-3.50000000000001,-0.470713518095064,3.87288227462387));
#533=CARTESIAN_POINT('',(-3.50000000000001,-0.235495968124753,3.88566728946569));
#534=CARTESIAN_POINT('',(-3.50000000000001,-0.117746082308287,3.88867616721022));
#535=CARTESIAN_POINT('',(-3.50000000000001,0.,3.88866958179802));
#536=B_SPLINE_CURVE_WITH_KNOTS('',3,(#424,#425,#426,#427,#428,#429,#430,#431,#432,#433,#434,
#435,#436,#437,#438,#439,#440,#441,#442,#443,#444,#445,#446,#447,#448,#449,#450,#451,#452,#453,
#454,#455,#456,#457,#458,#459,#460,#461,#462,#463,#464,#465,#466,#467,#468,#469,#470,#471,#472,
#473,#474,#475,#476,#477,#478,#479,#480,#481,#482,#483,#484,#485,#486,#487,#488,#489,#490,#491,
#492,#493,#494,#495,#496,#497,#498,#499,#500,#501,#502,#503,#504,#505,#506,#507,#508,#509,#510,
#511,#512,#513,#514,#515,#516,#517,#518,#519,#520,#521,#522,#523,#524,#525,#526,#527,#528,#529,
#530,#531,#532,#533,#534,#535),.UNSPECIFIED.,.T.,.F.,(4,2,2,2,2,2,2,2,2,2,2,2,2,2,2,2,2,2,2,2,2,
2,2,2,2,2,2,2,2,2,2,2,2,2,2,2,2,2,2,2,2,2,2,2,2,2,2,2,2,2,2,2,2,2,2,4),(0.,0.25896048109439,
0.518002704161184,0.776503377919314,1.034819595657,1.25457530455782,1.4748459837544,
1.69832240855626,1.92049274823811,2.0260391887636,2.13157634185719,2.23830124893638,
2.34486061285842,2.43787441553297,2.53088609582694,2.61595499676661,2.70104191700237,
2.82672538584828,2.95274915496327,3.15085859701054,3.34920453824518,3.54319361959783,
3.73738982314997,3.93291697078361,4.12833042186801,4.36394350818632,4.59962039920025,
4.83591542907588,5.07217313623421,5.30658695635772,5.54108389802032,5.77468204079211,
6.00805779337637,6.11615522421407,6.22428678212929,6.44013860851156,6.59875051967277,
6.75712816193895,6.86485155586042,6.97241137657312,7.06214192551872,7.15181960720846,
7.24182950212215,7.33184911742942,7.41683554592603,7.50185444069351,7.62640196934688,
7.75123947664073,7.94649755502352,8.14223757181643,8.33270789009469,8.52337608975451,
8.71428530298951,8.90526170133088,9.25858529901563,9.61179622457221),.UNSPECIFIED.);
#537=CARTESIAN_POINT('',(-3.50000000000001,2.02072594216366,3.));
#538=VERTEX_POINT('',#537);
#539=EDGE_CURVE('E131',#397,#538,#536,.T.);
#540=ORIENTED_EDGE('',*,*,#539,.T.);
#541=DIRECTION('',(0.,0.,-1.));
#542=VECTOR('',#541,1.);
#543=CARTESIAN_POINT('',(-3.50000000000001,2.02072594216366,4.));
#544=LINE('',#543,#542);
#545=CARTESIAN_POINT('',(-3.50000000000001,2.02072594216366,1.18087034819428));
#546=VERTEX_POINT('',#545);
#547=EDGE_CURVE('E112',#538,#546,#544,.T.);
#548=ORIENTED_EDGE('',*,*,#547,.T.);
#549=CARTESIAN_POINT('',(-3.50000000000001,0.,-24.25));
#550=DIRECTION('',(-1.,0.,0.));
#551=DIRECTION('',(0.,-1.,0.));
#552=AXIS2_PLACEMENT_3D('',#549,#550,#551);
#553=CIRCLE('',#552,25.5110270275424);
#554=EDGE_CURVE('E252',#546,#405,#553,.F.);
#555=ORIENTED_EDGE('',*,*,#554,.T.);
#556=EDGE_LOOP('',(#423,#540,#548,#555));
#557=FACE_BOUND('',#556,.T.);
#558=ADVANCED_FACE('F185',(#557),#422,.T.);
#559=CARTESIAN_POINT('',(-3.50000000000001,2.02072594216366,4.));
#560=DIRECTION('',(-0.500000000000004,0.866025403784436,0.));
#561=DIRECTION('',(-0.866025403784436,-0.500000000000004,0.));
#562=AXIS2_PLACEMENT_3D('',#559,#560,#561);
#563=PLANE('',#562);
#564=ORIENTED_EDGE('',*,*,#547,.F.);
#565=CARTESIAN_POINT('',(-3.499999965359,2.02072596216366,2.9998));
#566=CARTESIAN_POINT('',(-3.50006541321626,2.02068817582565,3.02946004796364));
#567=CARTESIAN_POINT('',(-3.497738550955,2.02203159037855,3.05905658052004));
#568=CARTESIAN_POINT('',(-3.48877331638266,2.02720767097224,3.11713737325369));
#569=CARTESIAN_POINT('',(-3.48216877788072,2.03102080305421,3.14562851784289));
#570=CARTESIAN_POINT('',(-3.46512873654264,2.04085887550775,3.20093447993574));
#571=CARTESIAN_POINT('',(-3.45470238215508,2.04687853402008,3.22775312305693));
#572=CARTESIAN_POINT('',(-3.43063992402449,2.06077100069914,3.27943202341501));
#573=CARTESIAN_POINT('',(-3.41699729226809,2.06864757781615,3.30428815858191));
#574=CARTESIAN_POINT('',(-3.37857137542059,2.09083279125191,3.36543474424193));
#575=CARTESIAN_POINT('',(-3.35188084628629,2.10624257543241,3.40012716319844));
#576=CARTESIAN_POINT('',(-3.2941277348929,2.13958634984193,3.46423943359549));
#577=CARTESIAN_POINT('',(-3.26305460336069,2.15752643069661,3.49364616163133));
#578=CARTESIAN_POINT('',(-3.17696368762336,2.20723104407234,3.56519618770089));
#579=CARTESIAN_POINT('',(-3.11944581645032,2.24043900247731,3.60329409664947));
#580=CARTESIAN_POINT('',(-3.000331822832,2.3092094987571,3.66943708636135));
#581=CARTESIAN_POINT('',(-2.93872771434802,2.34477664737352,3.69746175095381));
#582=CARTESIAN_POINT('',(-2.79342836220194,2.42866526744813,3.75351666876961));
#583=CARTESIAN_POINT('',(-2.70893292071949,2.47744873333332,3.77871981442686));
#584=CARTESIAN_POINT('',(-2.53819605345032,2.57602370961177,3.81977186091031));
#585=CARTESIAN_POINT('',(-2.45195123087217,2.62581718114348,3.83560030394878));
#586=CARTESIAN_POINT('',(-2.27807380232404,2.72620536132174,3.8605608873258));
#587=CARTESIAN_POINT('',(-2.19043561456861,2.77680329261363,3.86963887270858));
#588=CARTESIAN_POINT('',(-2.01497662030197,2.87810459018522,3.88252309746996));
#589=CARTESIAN_POINT('',(-1.92715607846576,2.92880780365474,3.88633451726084));
#590=CARTESIAN_POINT('',(-1.74407122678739,3.03451189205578,3.88956421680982));
#591=CARTESIAN_POINT('',(-1.64880182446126,3.08951570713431,3.88858622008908));
#592=CARTESIAN_POINT('',(-1.45831651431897,3.19949245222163,3.88109833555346));
#593=CARTESIAN_POINT('',(-1.36310075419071,3.25446529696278,3.87458294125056));
#594=CARTESIAN_POINT('',(-1.17405890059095,3.36360866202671,3.85466572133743));
#595=CARTESIAN_POINT('',(-1.08022803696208,3.41778193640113,3.84132691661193));
#596=CARTESIAN_POINT('',(-0.894006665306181,3.52529689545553,3.80514232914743));
#597=CARTESIAN_POINT('',(-0.801613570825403,3.57864007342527,3.78231634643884));
#598=CARTESIAN_POINT('',(-0.663179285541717,3.65856514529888,3.73693902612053));
#599=CARTESIAN_POINT('',(-0.615921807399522,3.6858492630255,3.71938388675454));
#600=CARTESIAN_POINT('',(-0.522814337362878,3.73960488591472,3.67952045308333));
#601=CARTESIAN_POINT('',(-0.476966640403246,3.76607506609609,3.65720483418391));
#602=CARTESIAN_POINT('',(-0.387312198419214,3.81783708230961,3.60659866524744));
#603=CARTESIAN_POINT('',(-0.343524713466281,3.84311779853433,3.57826174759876));
#604=CARTESIAN_POINT('',(-0.25997627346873,3.89135451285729,3.51449392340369));
#605=CARTESIAN_POINT('',(-0.220206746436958,3.91431545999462,3.47907862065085));
#606=CARTESIAN_POINT('',(-0.160686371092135,3.94867956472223,3.41460554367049));
#607=CARTESIAN_POINT('',(-0.138952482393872,3.96122763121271,3.38800019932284));
#608=CARTESIAN_POINT('',(-0.0990712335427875,3.9842530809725,3.33138585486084));
#609=CARTESIAN_POINT('',(-0.0809205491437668,3.99473238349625,3.30138005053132));
#610=CARTESIAN_POINT('',(-0.0516575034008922,4.01162741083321,3.24278652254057));
#611=CARTESIAN_POINT('',(-0.0399052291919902,4.01841258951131,3.2146280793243));
#612=CARTESIAN_POINT('',(-0.0206385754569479,4.02953619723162,3.15645553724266));
#613=CARTESIAN_POINT('',(-0.0131151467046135,4.03387985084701,3.12644555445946));
#614=CARTESIAN_POINT('',(-0.00534902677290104,4.03836362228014,3.08009860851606));
#615=CARTESIAN_POINT('',(-0.00334490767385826,4.03952070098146,3.06413628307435));
#616=CARTESIAN_POINT('',(-0.000665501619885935,4.04106765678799,3.03205266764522));
#617=CARTESIAN_POINT('',(8.84533406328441E-06,4.04145699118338,3.01593127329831));
#618=CARTESIAN_POINT('',(-3.46410179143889E-08,4.04145186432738,2.9998));
#619=B_SPLINE_CURVE_WITH_KNOTS('',3,(#565,#566,#567,#568,#569,#570,#571,#572,#573,#574,#575,
#576,#577,#578,#579,#580,#581,#582,#583,#584,#585,#586,#587,#588,#589,#590,#591,#592,#593,#594,
#595,#596,#597,#598,#599,#600,#601,#602,#603,#604,#605,#606,#607,#608,#609,#610,#611,#612,#613,
#614,#615,#616,#617,#618),.UNSPECIFIED.,.F.,.F.,(4,2,2,2,2,2,2,2,2,2,2,2,2,2,2,2,2,2,2,2,2,2,2,
2,2,2,4),(0.,0.0887549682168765,0.176816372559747,0.264668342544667,0.352700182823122,
0.491116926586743,0.62987272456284,0.858271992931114,1.08713159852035,1.38870326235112,
1.69093062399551,1.99555716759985,2.29988385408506,2.62979570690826,2.96003601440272,
3.28727986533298,3.61384415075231,3.78564861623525,3.95771935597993,4.13116655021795,
4.30423552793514,4.41365097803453,4.52296443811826,4.61636709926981,4.70956912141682,
4.75789060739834,4.80624623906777),.UNSPECIFIED.);
#620=EDGE_CURVE('E37',#538,#29,#619,.T.);
#621=ORIENTED_EDGE('',*,*,#620,.T.);
#622=ORIENTED_EDGE('',*,*,#32,.T.);
#623=CARTESIAN_POINT('',(-1.75000000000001,3.03108891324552,-24.25));
#624=DIRECTION('',(-0.500000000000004,0.866025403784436,0.));
#625=DIRECTION('',(-0.866025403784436,-0.500000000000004,0.));
#626=AXIS2_PLACEMENT_3D('',#623,#624,#625);
#627=CIRCLE('',#626,25.5110270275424);
#628=EDGE_CURVE('E250',#31,#546,#627,.F.);
#629=ORIENTED_EDGE('',*,*,#628,.T.);
#630=EDGE_LOOP('',(#564,#621,#622,#629));
#631=FACE_BOUND('',#630,.T.);
#632=ADVANCED_FACE('F30',(#631),#563,.T.);
#633=CARTESIAN_POINT('',(0.,4.04145188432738,0.));
#634=DIRECTION('',(0.,0.,-1.));
#635=DIRECTION('',(-1.,0.,0.));
#636=AXIS2_PLACEMENT_3D('',#633,#634,#635);
#637=PLANE('',#636);
#638=CARTESIAN_POINT('',(0.,0.,0.));
#639=DIRECTION('',(0.,0.,-1.));
#640=DIRECTION('',(-1.,0.,0.));
#641=AXIS2_PLACEMENT_3D('',#638,#639,#640);
#642=CIRCLE('',#641,2.);
#643=CARTESIAN_POINT('',(-2.,0.,0.));
#644=VERTEX_POINT('',#643);
#645=EDGE_CURVE('E108',#644,#644,#642,.T.);
#646=ORIENTED_EDGE('',*,*,#645,.F.);
#647=EDGE_LOOP('',(#646));
#648=FACE_BOUND('',#647,.T.);
#649=CARTESIAN_POINT('',(0.,0.,0.));
#650=DIRECTION('',(0.,0.,-1.));
#651=DIRECTION('',(-1.,0.,0.));
#652=AXIS2_PLACEMENT_3D('',#649,#650,#651);
#653=CIRCLE('',#652,5.);
#654=CARTESIAN_POINT('',(-5.,0.,0.));
#655=VERTEX_POINT('',#654);
#656=EDGE_CURVE('E94',#655,#655,#653,.T.);
#657=ORIENTED_EDGE('',*,*,#656,.T.);
#658=EDGE_LOOP('',(#657));
#659=FACE_BOUND('',#658,.T.);
#660=ADVANCED_FACE('F197',(#648,#659),#637,.T.);
#661=CARTESIAN_POINT('',(0.,0.,-20.));
#662=DIRECTION('',(0.,0.,1.));
#663=DIRECTION('',(1.,0.,0.));
#664=AXIS2_PLACEMENT_3D('',#661,#662,#663);
#665=CYLINDRICAL_SURFACE('',#664,2.);
#666=CARTESIAN_POINT('',(0.,0.,-20.));
#667=DIRECTION('',(0.,0.,1.));
#668=DIRECTION('',(1.,0.,0.));
#669=AXIS2_PLACEMENT_3D('',#666,#667,#668);
#670=CIRCLE('',#669,2.);
#671=CARTESIAN_POINT('',(2.,0.,-20.));
#672=VERTEX_POINT('',#671);
#673=EDGE_CURVE('E104',#672,#672,#670,.T.);
#674=ORIENTED_EDGE('',*,*,#673,.T.);
#675=EDGE_LOOP('',(#674));
#676=FACE_BOUND('',#675,.T.);
#677=ORIENTED_EDGE('',*,*,#645,.T.);
#678=EDGE_LOOP('',(#677));
#679=FACE_BOUND('',#678,.T.);
#680=ADVANCED_FACE('F275',(#676,#679),#665,.T.);
#681=CARTESIAN_POINT('',(0.,0.,-20.));
#682=DIRECTION('',(0.,0.,1.));
#683=DIRECTION('',(1.,0.,0.));
#684=AXIS2_PLACEMENT_3D('',#681,#682,#683);
#685=PLANE('',#684);
#686=ORIENTED_EDGE('',*,*,#673,.F.);
#687=EDGE_LOOP('',(#686));
#688=FACE_BOUND('',#687,.T.);
#689=ADVANCED_FACE('F267',(#688),#685,.F.);
#690=CARTESIAN_POINT('',(0.,0.,-24.25));
#691=DIRECTION('',(0.,0.,-1.));
#692=DIRECTION('',(1.,0.,0.));
#693=AXIS2_PLACEMENT_3D('',#690,#691,#692);
#694=SPHERICAL_SURFACE('',#693,25.75);
#695=ORIENTED_EDGE('',*,*,#628,.F.);
#696=ORIENTED_EDGE('',*,*,#106,.F.);
#697=ORIENTED_EDGE('',*,*,#247,.F.);
#698=ORIENTED_EDGE('',*,*,#330,.F.);
#699=ORIENTED_EDGE('',*,*,#413,.F.);
#700=ORIENTED_EDGE('',*,*,#554,.F.);
#701=EDGE_LOOP('',(#695,#696,#697,#698,#699,#700));
#702=FACE_BOUND('',#701,.T.);
#703=CARTESIAN_POINT('',(0.,0.,0.990099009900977));
#704=DIRECTION('',(0.,0.,-1.));
#705=DIRECTION('',(-1.,0.,0.));
#706=AXIS2_PLACEMENT_3D('',#703,#704,#705);
#707=CIRCLE('',#706,5.0990099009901);
#708=CARTESIAN_POINT('',(-5.0990099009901,0.,0.990099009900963));
#709=VERTEX_POINT('',#708);
#710=EDGE_CURVE('E259',#709,#709,#707,.T.);
#711=ORIENTED_EDGE('',*,*,#710,.F.);
#712=EDGE_LOOP('',(#711));
#713=FACE_BOUND('',#712,.T.);
#714=ADVANCED_FACE('F265',(#702,#713),#694,.T.);
#715=CARTESIAN_POINT('',(0.,0.,0.499999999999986));
#716=DIRECTION('',(0.,0.,-1.));
#717=DIRECTION('',(-1.,0.,0.));
#718=AXIS2_PLACEMENT_3D('',#715,#716,#717);
#719=TOROIDAL_SURFACE('',#718,5.,0.500000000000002);
#720=ORIENTED_EDGE('',*,*,#710,.T.);
#721=EDGE_LOOP('',(#720));
#722=FACE_BOUND('',#721,.T.);
#723=ORIENTED_EDGE('',*,*,#656,.F.);
#724=EDGE_LOOP('',(#723));
#725=FACE_BOUND('',#724,.T.);
#726=ADVANCED_FACE('F122',(#722,#725),#719,.T.);
#727=CARTESIAN_POINT('',(0.,0.,3.));
#728=DIRECTION('',(0.,0.,1.));
#729=DIRECTION('',(1.,0.,0.));
#730=AXIS2_PLACEMENT_3D('',#727,#728,#729);
#731=TOROIDAL_SURFACE('',#730,3.04145188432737,1.);
#732=ORIENTED_EDGE('',*,*,#620,.F.);
#733=ORIENTED_EDGE('',*,*,#539,.F.);
#734=ORIENTED_EDGE('',*,*,#398,.F.);
#735=ORIENTED_EDGE('',*,*,#315,.F.);
#736=ORIENTED_EDGE('',*,*,#232,.F.);
#737=ORIENTED_EDGE('',*,*,#91,.F.);
#738=EDGE_LOOP('',(#732,#733,#734,#735,#736,#737));
#739=FACE_BOUND('',#738,.T.);
#740=CARTESIAN_POINT('',(0.,0.,4.));
#741=DIRECTION('',(0.,0.,1.));
#742=DIRECTION('',(1.,0.,0.));
#743=AXIS2_PLACEMENT_3D('',#740,#741,#742);
#744=CIRCLE('',#743,3.04145188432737);
#745=CARTESIAN_POINT('',(3.04145188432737,0.,4.));
#746=VERTEX_POINT('',#745);
#747=EDGE_CURVE('E229',#746,#746,#744,.T.);
#748=ORIENTED_EDGE('',*,*,#747,.F.);
#749=EDGE_LOOP('',(#748));
#750=FACE_BOUND('',#749,.T.);
#751=ADVANCED_FACE('F82',(#739,#750),#731,.T.);
#752=CARTESIAN_POINT('',(0.,4.04145188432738,4.));
#753=DIRECTION('',(0.,0.,-1.));
#754=DIRECTION('',(-1.,0.,0.));
#755=AXIS2_PLACEMENT_3D('',#752,#753,#754);
#756=PLANE('',#755);
#757=CARTESIAN_POINT('',(0.,0.,4.));
#758=DIRECTION('',(0.,0.,1.));
#759=DIRECTION('',(1.,0.,0.));
#760=AXIS2_PLACEMENT_3D('',#757,#758,#759);
#761=CIRCLE('',#760,2.625);
#762=CARTESIAN_POINT('',(2.625,0.,4.));
#763=VERTEX_POINT('',#762);
#764=EDGE_CURVE('E227',#763,#763,#761,.T.);
#765=ORIENTED_EDGE('',*,*,#764,.F.);
#766=EDGE_LOOP('',(#765));
#767=FACE_BOUND('',#766,.T.);
#768=ORIENTED_EDGE('',*,*,#747,.T.);
#769=EDGE_LOOP('',(#768));
#770=FACE_BOUND('',#769,.T.);
#771=ADVANCED_FACE('F121',(#767,#770),#756,.F.);
#772=CARTESIAN_POINT('',(0.,0.,3.));
#773=DIRECTION('',(0.,0.,1.));
#774=DIRECTION('',(1.,0.,0.));
#775=AXIS2_PLACEMENT_3D('',#772,#773,#774);
#776=PLANE('',#775);
#777=CARTESIAN_POINT('',(0.,0.,3.));
#778=DIRECTION('',(0.,0.,1.));
#779=DIRECTION('',(1.,0.,0.));
#780=AXIS2_PLACEMENT_3D('',#777,#778,#779);
#781=CIRCLE('',#780,1.625);
#782=CARTESIAN_POINT('',(1.625,0.,3.));
#783=VERTEX_POINT('',#782);
#784=EDGE_CURVE('E11',#783,#783,#781,.T.);
#785=ORIENTED_EDGE('',*,*,#784,.T.);
#786=EDGE_LOOP('',(#785));
#787=FACE_BOUND('',#786,.T.);
#788=ADVANCED_FACE('F123',(#787),#776,.T.);
#789=CARTESIAN_POINT('',(0.,0.,4.));
#790=DIRECTION('',(0.,0.,1.));
#791=DIRECTION('',(1.,0.,0.));
#792=AXIS2_PLACEMENT_3D('',#789,#790,#791);
#793=TOROIDAL_SURFACE('',#792,1.625,1.);
#794=ORIENTED_EDGE('',*,*,#764,.T.);
#795=EDGE_LOOP('',(#794));
#796=FACE_BOUND('',#795,.T.);
#797=ORIENTED_EDGE('',*,*,#784,.F.);
#798=EDGE_LOOP('',(#797));
#799=FACE_BOUND('',#798,.T.);
#800=ADVANCED_FACE('F215',(#796,#799),#793,.F.);
#801=CLOSED_SHELL('',(#110,#251,#334,#417,#558,#632,#660,#680,#689,#714,#726,#751,#771,#788,#800));
#802=MANIFOLD_SOLID_BREP('B2',#801);
#803=ADVANCED_BREP_SHAPE_REPRESENTATION('',(#18,#802),#14);
#804=SHAPE_DEFINITION_REPRESENTATION(#9,#803);
ENDSEC;
END-ISO-10303-21;
